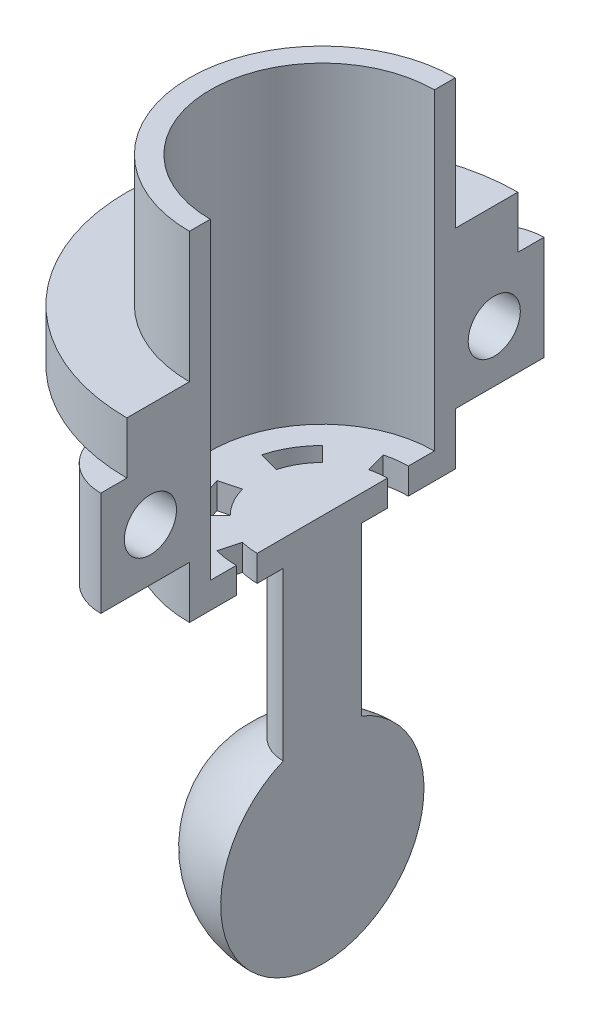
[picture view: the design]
ISO-10303-21;
HEADER;
FILE_DESCRIPTION(('STEP AP214'),'2;1');
FILE_NAME('part.step','',(''),(''),'','','');
FILE_SCHEMA(('AUTOMOTIVE_DESIGN { 1 0 10303 214 1 1 1 1 }'));
ENDSEC;
DATA;
#1=APPLICATION_CONTEXT('core data for automotive mechanical design processes');
#2=APPLICATION_PROTOCOL_DEFINITION('international standard','automotive_design',2000,#1);
#3=PRODUCT_CONTEXT('',#1,'mechanical');
#4=PRODUCT('Part','Part','',(#3));
#5=PRODUCT_RELATED_PRODUCT_CATEGORY('part','',(#4));
#6=PRODUCT_DEFINITION_FORMATION('','',#4);
#7=PRODUCT_DEFINITION_CONTEXT('part definition',#1,'design');
#8=PRODUCT_DEFINITION('design','',#6,#7);
#9=PRODUCT_DEFINITION_SHAPE('','',#8);
#10=(LENGTH_UNIT() NAMED_UNIT(*) SI_UNIT(.MILLI.,.METRE.));
#11=(NAMED_UNIT(*) PLANE_ANGLE_UNIT() SI_UNIT($,.RADIAN.));
#12=(NAMED_UNIT(*) SI_UNIT($,.STERADIAN.) SOLID_ANGLE_UNIT());
#13=UNCERTAINTY_MEASURE_WITH_UNIT(LENGTH_MEASURE(1.E-05),#10,'distance_accuracy_value','');
#14=(GEOMETRIC_REPRESENTATION_CONTEXT(3) GLOBAL_UNCERTAINTY_ASSIGNED_CONTEXT((#13)) GLOBAL_UNIT_ASSIGNED_CONTEXT((#10,
#11,#12)) REPRESENTATION_CONTEXT('',''));
#15=CARTESIAN_POINT('',(0.,0.,0.));
#16=DIRECTION('',(0.,0.,1.));
#17=DIRECTION('',(1.,0.,0.));
#18=AXIS2_PLACEMENT_3D('',#15,#16,#17);
#19=CARTESIAN_POINT('',(0.,0.,0.));
#20=DIRECTION('',(1.,0.,0.));
#21=DIRECTION('',(0.,0.,-1.));
#22=AXIS2_PLACEMENT_3D('',#19,#20,#21);
#23=PLANE('',#22);
#24=DIRECTION('',(0.,0.,-1.));
#25=VECTOR('',#24,1.);
#26=CARTESIAN_POINT('',(0.,1.,0.));
#27=LINE('',#26,#25);
#28=CARTESIAN_POINT('',(0.,1.,2.5));
#29=VERTEX_POINT('',#28);
#30=CARTESIAN_POINT('',(0.,1.,-2.5));
#31=VERTEX_POINT('',#30);
#32=EDGE_CURVE('E470',#29,#31,#27,.T.);
#33=ORIENTED_EDGE('',*,*,#32,.F.);
#34=DIRECTION('',(0.,1.,0.));
#35=VECTOR('',#34,1.);
#36=CARTESIAN_POINT('',(0.,0.,2.5));
#37=LINE('',#36,#35);
#38=CARTESIAN_POINT('',(0.,0.,2.5));
#39=VERTEX_POINT('',#38);
#40=EDGE_CURVE('E451',#39,#29,#37,.T.);
#41=ORIENTED_EDGE('',*,*,#40,.F.);
#42=DIRECTION('',(0.,0.,-1.));
#43=VECTOR('',#42,1.);
#44=CARTESIAN_POINT('',(0.,0.,0.));
#45=LINE('',#44,#43);
#46=CARTESIAN_POINT('',(0.,0.,1.5));
#47=VERTEX_POINT('',#46);
#48=EDGE_CURVE('E663',#39,#47,#45,.T.);
#49=ORIENTED_EDGE('',*,*,#48,.T.);
#50=DIRECTION('',(0.,1.,0.));
#51=VECTOR('',#50,1.);
#52=CARTESIAN_POINT('',(0.,0.,1.5));
#53=LINE('',#52,#51);
#54=CARTESIAN_POINT('',(0.,-6.4,1.5));
#55=VERTEX_POINT('',#54);
#56=EDGE_CURVE('E437',#55,#47,#53,.T.);
#57=ORIENTED_EDGE('',*,*,#56,.F.);
#58=CARTESIAN_POINT('',(0.,-10.,0.));
#59=DIRECTION('',(1.,0.,0.));
#60=DIRECTION('',(0.,0.,-1.));
#61=AXIS2_PLACEMENT_3D('',#58,#59,#60);
#62=CIRCLE('',#61,3.9);
#63=CARTESIAN_POINT('',(0.,-6.4,-1.5));
#64=VERTEX_POINT('',#63);
#65=EDGE_CURVE('E434',#64,#55,#62,.F.);
#66=ORIENTED_EDGE('',*,*,#65,.F.);
#67=DIRECTION('',(0.,1.,0.));
#68=VECTOR('',#67,1.);
#69=CARTESIAN_POINT('',(0.,0.,-1.5));
#70=LINE('',#69,#68);
#71=CARTESIAN_POINT('',(0.,0.,-1.5));
#72=VERTEX_POINT('',#71);
#73=EDGE_CURVE('E440',#72,#64,#70,.F.);
#74=ORIENTED_EDGE('',*,*,#73,.F.);
#75=CARTESIAN_POINT('',(0.,0.,-2.5));
#76=VERTEX_POINT('',#75);
#77=EDGE_CURVE('E484',#72,#76,#45,.T.);
#78=ORIENTED_EDGE('',*,*,#77,.T.);
#79=DIRECTION('',(0.,1.,0.));
#80=VECTOR('',#79,1.);
#81=CARTESIAN_POINT('',(0.,0.,-2.5));
#82=LINE('',#81,#80);
#83=EDGE_CURVE('E448',#31,#76,#82,.F.);
#84=ORIENTED_EDGE('',*,*,#83,.F.);
#85=EDGE_LOOP('',(#33,#41,#49,#57,#66,#74,#78,#84));
#86=FACE_BOUND('',#85,.T.);
#87=ADVANCED_FACE('F47',(#86),#23,.T.);
#88=CARTESIAN_POINT('',(0.,0.,5.1));
#89=VERTEX_POINT('',#88);
#90=CARTESIAN_POINT('',(0.,0.,3.3));
#91=VERTEX_POINT('',#90);
#92=EDGE_CURVE('E479',#89,#91,#45,.T.);
#93=ORIENTED_EDGE('',*,*,#92,.T.);
#94=DIRECTION('',(0.,1.,0.));
#95=VECTOR('',#94,1.);
#96=CARTESIAN_POINT('',(0.,0.,3.3));
#97=LINE('',#96,#95);
#98=CARTESIAN_POINT('',(0.,1.,3.3));
#99=VERTEX_POINT('',#98);
#100=EDGE_CURVE('E493',#91,#99,#97,.T.);
#101=ORIENTED_EDGE('',*,*,#100,.T.);
#102=CARTESIAN_POINT('',(0.,1.,4.3));
#103=VERTEX_POINT('',#102);
#104=EDGE_CURVE('E466',#103,#99,#27,.T.);
#105=ORIENTED_EDGE('',*,*,#104,.F.);
#106=DIRECTION('',(0.,-1.,0.));
#107=VECTOR('',#106,1.);
#108=CARTESIAN_POINT('',(0.,13.,4.3));
#109=LINE('',#108,#107);
#110=CARTESIAN_POINT('',(0.,13.,4.3));
#111=VERTEX_POINT('',#110);
#112=EDGE_CURVE('E462',#111,#103,#109,.T.);
#113=ORIENTED_EDGE('',*,*,#112,.F.);
#114=DIRECTION('',(0.,0.,-1.));
#115=VECTOR('',#114,1.);
#116=CARTESIAN_POINT('',(0.,13.,0.));
#117=LINE('',#116,#115);
#118=CARTESIAN_POINT('',(0.,13.,5.1));
#119=VERTEX_POINT('',#118);
#120=EDGE_CURVE('E455',#119,#111,#117,.T.);
#121=ORIENTED_EDGE('',*,*,#120,.F.);
#122=DIRECTION('',(0.,-1.,0.));
#123=VECTOR('',#122,1.);
#124=CARTESIAN_POINT('',(0.,1.,5.1));
#125=LINE('',#124,#123);
#126=CARTESIAN_POINT('',(0.,8.,5.1));
#127=VERTEX_POINT('',#126);
#128=EDGE_CURVE('E485',#119,#127,#125,.T.);
#129=ORIENTED_EDGE('',*,*,#128,.T.);
#130=DIRECTION('',(0.,0.,-1.));
#131=VECTOR('',#130,1.);
#132=CARTESIAN_POINT('',(0.,8.,0.));
#133=LINE('',#132,#131);
#134=CARTESIAN_POINT('',(0.,8.,7.5));
#135=VERTEX_POINT('',#134);
#136=EDGE_CURVE('E445',#135,#127,#133,.T.);
#137=ORIENTED_EDGE('',*,*,#136,.F.);
#138=DIRECTION('',(0.,-1.,0.));
#139=VECTOR('',#138,1.);
#140=CARTESIAN_POINT('',(0.,8.,7.5));
#141=LINE('',#140,#139);
#142=CARTESIAN_POINT('',(0.,6.,7.5));
#143=VERTEX_POINT('',#142);
#144=EDGE_CURVE('E299',#135,#143,#141,.T.);
#145=ORIENTED_EDGE('',*,*,#144,.T.);
#146=DIRECTION('',(0.,0.,-1.));
#147=VECTOR('',#146,1.);
#148=CARTESIAN_POINT('',(0.,6.,-7.502));
#149=LINE('',#148,#147);
#150=CARTESIAN_POINT('',(0.,6.,8.5));
#151=VERTEX_POINT('',#150);
#152=EDGE_CURVE('E427',#151,#143,#149,.T.);
#153=ORIENTED_EDGE('',*,*,#152,.F.);
#154=DIRECTION('',(0.,1.,0.));
#155=VECTOR('',#154,1.);
#156=CARTESIAN_POINT('',(0.,6.,8.5));
#157=LINE('',#156,#155);
#158=CARTESIAN_POINT('',(0.,2.,8.5));
#159=VERTEX_POINT('',#158);
#160=EDGE_CURVE('E409',#159,#151,#157,.T.);
#161=ORIENTED_EDGE('',*,*,#160,.F.);
#162=DIRECTION('',(0.,0.,1.));
#163=VECTOR('',#162,1.);
#164=CARTESIAN_POINT('',(0.,2.,-7.502));
#165=LINE('',#164,#163);
#166=CARTESIAN_POINT('',(0.,2.,5.1));
#167=VERTEX_POINT('',#166);
#168=EDGE_CURVE('E431',#167,#159,#165,.T.);
#169=ORIENTED_EDGE('',*,*,#168,.F.);
#170=DIRECTION('',(0.,-1.,0.));
#171=VECTOR('',#170,1.);
#172=CARTESIAN_POINT('',(0.,1.,5.1));
#173=LINE('',#172,#171);
#174=EDGE_CURVE('E471',#167,#89,#173,.T.);
#175=ORIENTED_EDGE('',*,*,#174,.T.);
#176=EDGE_LOOP('',(#93,#101,#105,#113,#121,#129,#137,#145,#153,#161,#169,#175));
#177=FACE_BOUND('',#176,.T.);
#178=CARTESIAN_POINT('',(0.,4.,6.59574082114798));
#179=DIRECTION('',(1.,0.,0.));
#180=DIRECTION('',(0.,1.,0.));
#181=AXIS2_PLACEMENT_3D('',#178,#179,#180);
#182=CIRCLE('',#181,1.);
#183=CARTESIAN_POINT('',(0.,5.,6.59574082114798));
#184=VERTEX_POINT('',#183);
#185=EDGE_CURVE('E405',#184,#184,#182,.T.);
#186=ORIENTED_EDGE('',*,*,#185,.F.);
#187=EDGE_LOOP('',(#186));
#188=FACE_BOUND('',#187,.T.);
#189=ADVANCED_FACE('F508',(#177,#188),#23,.T.);
#190=CARTESIAN_POINT('',(0.,1.,-3.3));
#191=VERTEX_POINT('',#190);
#192=CARTESIAN_POINT('',(0.,1.,-4.3));
#193=VERTEX_POINT('',#192);
#194=EDGE_CURVE('E465',#191,#193,#27,.T.);
#195=ORIENTED_EDGE('',*,*,#194,.F.);
#196=DIRECTION('',(0.,1.,0.));
#197=VECTOR('',#196,1.);
#198=CARTESIAN_POINT('',(0.,0.,-3.3));
#199=LINE('',#198,#197);
#200=CARTESIAN_POINT('',(0.,0.,-3.3));
#201=VERTEX_POINT('',#200);
#202=EDGE_CURVE('E497',#191,#201,#199,.F.);
#203=ORIENTED_EDGE('',*,*,#202,.T.);
#204=CARTESIAN_POINT('',(0.,0.,-5.1));
#205=VERTEX_POINT('',#204);
#206=EDGE_CURVE('E480',#201,#205,#45,.T.);
#207=ORIENTED_EDGE('',*,*,#206,.T.);
#208=DIRECTION('',(0.,-1.,0.));
#209=VECTOR('',#208,1.);
#210=CARTESIAN_POINT('',(0.,1.,-5.1));
#211=LINE('',#210,#209);
#212=CARTESIAN_POINT('',(0.,2.,-5.1));
#213=VERTEX_POINT('',#212);
#214=EDGE_CURVE('E475',#205,#213,#211,.F.);
#215=ORIENTED_EDGE('',*,*,#214,.T.);
#216=DIRECTION('',(0.,0.,-1.));
#217=VECTOR('',#216,1.);
#218=CARTESIAN_POINT('',(0.,2.,8.502));
#219=LINE('',#218,#217);
#220=CARTESIAN_POINT('',(0.,2.,-8.5));
#221=VERTEX_POINT('',#220);
#222=EDGE_CURVE('E300',#213,#221,#219,.T.);
#223=ORIENTED_EDGE('',*,*,#222,.T.);
#224=DIRECTION('',(0.,1.,0.));
#225=VECTOR('',#224,1.);
#226=CARTESIAN_POINT('',(0.,0.,-8.5));
#227=LINE('',#226,#225);
#228=CARTESIAN_POINT('',(0.,6.,-8.5));
#229=VERTEX_POINT('',#228);
#230=EDGE_CURVE('E11',#229,#221,#227,.F.);
#231=ORIENTED_EDGE('',*,*,#230,.F.);
#232=DIRECTION('',(0.,0.,1.));
#233=VECTOR('',#232,1.);
#234=CARTESIAN_POINT('',(0.,6.,8.502));
#235=LINE('',#234,#233);
#236=CARTESIAN_POINT('',(0.,6.,-7.5));
#237=VERTEX_POINT('',#236);
#238=EDGE_CURVE('E281',#229,#237,#235,.T.);
#239=ORIENTED_EDGE('',*,*,#238,.T.);
#240=DIRECTION('',(0.,-1.,0.));
#241=VECTOR('',#240,1.);
#242=CARTESIAN_POINT('',(0.,8.,-7.5));
#243=LINE('',#242,#241);
#244=CARTESIAN_POINT('',(0.,8.,-7.5));
#245=VERTEX_POINT('',#244);
#246=EDGE_CURVE('E293',#237,#245,#243,.F.);
#247=ORIENTED_EDGE('',*,*,#246,.T.);
#248=CARTESIAN_POINT('',(0.,8.,-5.1));
#249=VERTEX_POINT('',#248);
#250=EDGE_CURVE('E444',#249,#245,#133,.T.);
#251=ORIENTED_EDGE('',*,*,#250,.F.);
#252=DIRECTION('',(0.,-1.,0.));
#253=VECTOR('',#252,1.);
#254=CARTESIAN_POINT('',(0.,1.,-5.1));
#255=LINE('',#254,#253);
#256=CARTESIAN_POINT('',(0.,13.,-5.1));
#257=VERTEX_POINT('',#256);
#258=EDGE_CURVE('E489',#249,#257,#255,.F.);
#259=ORIENTED_EDGE('',*,*,#258,.T.);
#260=CARTESIAN_POINT('',(0.,13.,-4.3));
#261=VERTEX_POINT('',#260);
#262=EDGE_CURVE('E454',#261,#257,#117,.T.);
#263=ORIENTED_EDGE('',*,*,#262,.F.);
#264=DIRECTION('',(0.,-1.,0.));
#265=VECTOR('',#264,1.);
#266=CARTESIAN_POINT('',(0.,13.,-4.3));
#267=LINE('',#266,#265);
#268=EDGE_CURVE('E458',#193,#261,#267,.F.);
#269=ORIENTED_EDGE('',*,*,#268,.F.);
#270=EDGE_LOOP('',(#195,#203,#207,#215,#223,#231,#239,#247,#251,#259,#263,#269));
#271=FACE_BOUND('',#270,.T.);
#272=CARTESIAN_POINT('',(0.,4.,-6.59574082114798));
#273=DIRECTION('',(-1.,0.,0.));
#274=DIRECTION('',(0.,1.,0.));
#275=AXIS2_PLACEMENT_3D('',#272,#273,#274);
#276=CIRCLE('',#275,1.);
#277=CARTESIAN_POINT('',(0.,5.,-6.59574082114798));
#278=VERTEX_POINT('',#277);
#279=EDGE_CURVE('E57',#278,#278,#276,.T.);
#280=ORIENTED_EDGE('',*,*,#279,.T.);
#281=EDGE_LOOP('',(#280));
#282=FACE_BOUND('',#281,.T.);
#283=ADVANCED_FACE('F303',(#271,#282),#23,.T.);
#284=CARTESIAN_POINT('',(0.,0.,0.));
#285=DIRECTION('',(0.,1.,0.));
#286=DIRECTION('',(0.,0.,1.));
#287=AXIS2_PLACEMENT_3D('',#284,#285,#286);
#288=CYLINDRICAL_SURFACE('',#287,3.3);
#289=CARTESIAN_POINT('',(0.,1.,0.));
#290=DIRECTION('',(0.,1.,0.));
#291=DIRECTION('',(0.,0.,1.));
#292=AXIS2_PLACEMENT_3D('',#289,#290,#291);
#293=CIRCLE('',#292,3.3);
#294=CARTESIAN_POINT('',(-2.33345237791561,1.,-2.33345237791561));
#295=VERTEX_POINT('',#294);
#296=CARTESIAN_POINT('',(-3.18755522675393,1.,-0.854102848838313));
#297=VERTEX_POINT('',#296);
#298=EDGE_CURVE('E585',#295,#297,#293,.T.);
#299=ORIENTED_EDGE('',*,*,#298,.T.);
#300=DIRECTION('',(0.,1.,0.));
#301=VECTOR('',#300,1.);
#302=CARTESIAN_POINT('',(-3.18755522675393,0.,-0.854102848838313));
#303=LINE('',#302,#301);
#304=CARTESIAN_POINT('',(-3.18755522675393,0.,-0.854102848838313));
#305=VERTEX_POINT('',#304);
#306=EDGE_CURVE('E614',#305,#297,#303,.T.);
#307=ORIENTED_EDGE('',*,*,#306,.F.);
#308=CARTESIAN_POINT('',(0.,0.,0.));
#309=DIRECTION('',(0.,1.,0.));
#310=DIRECTION('',(0.,0.,1.));
#311=AXIS2_PLACEMENT_3D('',#308,#309,#310);
#312=CIRCLE('',#311,3.3);
#313=CARTESIAN_POINT('',(-2.33345237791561,0.,-2.33345237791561));
#314=VERTEX_POINT('',#313);
#315=EDGE_CURVE('E599',#314,#305,#312,.T.);
#316=ORIENTED_EDGE('',*,*,#315,.F.);
#317=DIRECTION('',(0.,1.,0.));
#318=VECTOR('',#317,1.);
#319=CARTESIAN_POINT('',(-2.33345237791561,0.,-2.33345237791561));
#320=LINE('',#319,#318);
#321=EDGE_CURVE('E611',#314,#295,#320,.T.);
#322=ORIENTED_EDGE('',*,*,#321,.T.);
#323=EDGE_LOOP('',(#299,#307,#316,#322));
#324=FACE_BOUND('',#323,.T.);
#325=ADVANCED_FACE('F721',(#324),#288,.F.);
#326=CARTESIAN_POINT('',(0.,0.,0.));
#327=DIRECTION('',(-0.258819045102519,0.,0.965925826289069));
#328=DIRECTION('',(0.965925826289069,0.,0.258819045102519));
#329=AXIS2_PLACEMENT_3D('',#326,#327,#328);
#330=PLANE('',#329);
#331=DIRECTION('',(0.965925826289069,0.,0.258819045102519));
#332=VECTOR('',#331,1.);
#333=CARTESIAN_POINT('',(0.,1.,0.));
#334=LINE('',#333,#332);
#335=CARTESIAN_POINT('',(-2.41481456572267,1.,-0.647047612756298));
#336=VERTEX_POINT('',#335);
#337=EDGE_CURVE('E589',#297,#336,#334,.T.);
#338=ORIENTED_EDGE('',*,*,#337,.T.);
#339=DIRECTION('',(0.,1.,0.));
#340=VECTOR('',#339,1.);
#341=CARTESIAN_POINT('',(-2.41481456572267,0.,-0.647047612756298));
#342=LINE('',#341,#340);
#343=CARTESIAN_POINT('',(-2.41481456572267,0.,-0.647047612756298));
#344=VERTEX_POINT('',#343);
#345=EDGE_CURVE('E330',#344,#336,#342,.T.);
#346=ORIENTED_EDGE('',*,*,#345,.F.);
#347=DIRECTION('',(0.965925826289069,0.,0.258819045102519));
#348=VECTOR('',#347,1.);
#349=CARTESIAN_POINT('',(0.,0.,0.));
#350=LINE('',#349,#348);
#351=EDGE_CURVE('E603',#305,#344,#350,.T.);
#352=ORIENTED_EDGE('',*,*,#351,.F.);
#353=ORIENTED_EDGE('',*,*,#306,.T.);
#354=EDGE_LOOP('',(#338,#346,#352,#353));
#355=FACE_BOUND('',#354,.T.);
#356=ADVANCED_FACE('F723',(#355),#330,.F.);
#357=CARTESIAN_POINT('',(0.,0.,0.));
#358=DIRECTION('',(0.,1.,0.));
#359=DIRECTION('',(0.,0.,1.));
#360=AXIS2_PLACEMENT_3D('',#357,#358,#359);
#361=CYLINDRICAL_SURFACE('',#360,2.5);
#362=CARTESIAN_POINT('',(0.,1.,0.));
#363=DIRECTION('',(0.,1.,0.));
#364=DIRECTION('',(0.,0.,1.));
#365=AXIS2_PLACEMENT_3D('',#362,#363,#364);
#366=CIRCLE('',#365,2.5);
#367=CARTESIAN_POINT('',(-1.76776695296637,1.,-1.76776695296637));
#368=VERTEX_POINT('',#367);
#369=EDGE_CURVE('E336',#368,#336,#366,.T.);
#370=ORIENTED_EDGE('',*,*,#369,.F.);
#371=DIRECTION('',(0.,1.,0.));
#372=VECTOR('',#371,1.);
#373=CARTESIAN_POINT('',(-1.76776695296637,0.,-1.76776695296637));
#374=LINE('',#373,#372);
#375=CARTESIAN_POINT('',(-1.76776695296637,0.,-1.76776695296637));
#376=VERTEX_POINT('',#375);
#377=EDGE_CURVE('E607',#376,#368,#374,.T.);
#378=ORIENTED_EDGE('',*,*,#377,.F.);
#379=CARTESIAN_POINT('',(0.,0.,0.));
#380=DIRECTION('',(0.,1.,0.));
#381=DIRECTION('',(0.,0.,1.));
#382=AXIS2_PLACEMENT_3D('',#379,#380,#381);
#383=CIRCLE('',#382,2.5);
#384=EDGE_CURVE('E593',#376,#344,#383,.T.);
#385=ORIENTED_EDGE('',*,*,#384,.T.);
#386=ORIENTED_EDGE('',*,*,#345,.T.);
#387=EDGE_LOOP('',(#370,#378,#385,#386));
#388=FACE_BOUND('',#387,.T.);
#389=ADVANCED_FACE('F730',(#388),#361,.T.);
#390=CARTESIAN_POINT('',(0.,0.,0.));
#391=DIRECTION('',(-0.707106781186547,0.,0.707106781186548));
#392=DIRECTION('',(0.707106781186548,0.,0.707106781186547));
#393=AXIS2_PLACEMENT_3D('',#390,#391,#392);
#394=PLANE('',#393);
#395=DIRECTION('',(0.707106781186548,0.,0.707106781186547));
#396=VECTOR('',#395,1.);
#397=CARTESIAN_POINT('',(0.,1.,0.));
#398=LINE('',#397,#396);
#399=EDGE_CURVE('E581',#295,#368,#398,.T.);
#400=ORIENTED_EDGE('',*,*,#399,.F.);
#401=ORIENTED_EDGE('',*,*,#321,.F.);
#402=DIRECTION('',(0.707106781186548,0.,0.707106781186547));
#403=VECTOR('',#402,1.);
#404=CARTESIAN_POINT('',(0.,0.,0.));
#405=LINE('',#404,#403);
#406=EDGE_CURVE('E596',#314,#376,#405,.T.);
#407=ORIENTED_EDGE('',*,*,#406,.T.);
#408=ORIENTED_EDGE('',*,*,#377,.T.);
#409=EDGE_LOOP('',(#400,#401,#407,#408));
#410=FACE_BOUND('',#409,.T.);
#411=ADVANCED_FACE('F735',(#410),#394,.T.);
#412=CARTESIAN_POINT('',(0.,0.,0.));
#413=DIRECTION('',(0.,1.,0.));
#414=DIRECTION('',(0.,0.,1.));
#415=AXIS2_PLACEMENT_3D('',#412,#413,#414);
#416=CYLINDRICAL_SURFACE('',#415,3.3);
#417=CARTESIAN_POINT('',(0.,1.,0.));
#418=DIRECTION('',(0.,1.,0.));
#419=DIRECTION('',(0.,0.,1.));
#420=AXIS2_PLACEMENT_3D('',#417,#418,#419);
#421=CIRCLE('',#420,3.3);
#422=CARTESIAN_POINT('',(-3.18755522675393,1.,0.854102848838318));
#423=VERTEX_POINT('',#422);
#424=CARTESIAN_POINT('',(-2.3334523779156,1.,2.33345237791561));
#425=VERTEX_POINT('',#424);
#426=EDGE_CURVE('E557',#423,#425,#421,.T.);
#427=ORIENTED_EDGE('',*,*,#426,.T.);
#428=DIRECTION('',(0.,1.,0.));
#429=VECTOR('',#428,1.);
#430=CARTESIAN_POINT('',(-2.3334523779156,0.,2.33345237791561));
#431=LINE('',#430,#429);
#432=CARTESIAN_POINT('',(-2.3334523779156,0.,2.33345237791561));
#433=VERTEX_POINT('',#432);
#434=EDGE_CURVE('E529',#433,#425,#431,.T.);
#435=ORIENTED_EDGE('',*,*,#434,.F.);
#436=CARTESIAN_POINT('',(0.,0.,0.));
#437=DIRECTION('',(0.,1.,0.));
#438=DIRECTION('',(0.,0.,1.));
#439=AXIS2_PLACEMENT_3D('',#436,#437,#438);
#440=CIRCLE('',#439,3.3);
#441=CARTESIAN_POINT('',(-3.18755522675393,0.,0.854102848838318));
#442=VERTEX_POINT('',#441);
#443=EDGE_CURVE('E543',#442,#433,#440,.T.);
#444=ORIENTED_EDGE('',*,*,#443,.F.);
#445=DIRECTION('',(0.,1.,0.));
#446=VECTOR('',#445,1.);
#447=CARTESIAN_POINT('',(-3.18755522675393,0.,0.854102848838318));
#448=LINE('',#447,#446);
#449=EDGE_CURVE('E532',#442,#423,#448,.T.);
#450=ORIENTED_EDGE('',*,*,#449,.T.);
#451=EDGE_LOOP('',(#427,#435,#444,#450));
#452=FACE_BOUND('',#451,.T.);
#453=ADVANCED_FACE('F745',(#452),#416,.F.);
#454=CARTESIAN_POINT('',(0.,0.,0.));
#455=DIRECTION('',(0.707106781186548,0.,0.707106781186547));
#456=DIRECTION('',(0.707106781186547,0.,-0.707106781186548));
#457=AXIS2_PLACEMENT_3D('',#454,#455,#456);
#458=PLANE('',#457);
#459=DIRECTION('',(0.707106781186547,0.,-0.707106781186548));
#460=VECTOR('',#459,1.);
#461=CARTESIAN_POINT('',(0.,1.,0.));
#462=LINE('',#461,#460);
#463=CARTESIAN_POINT('',(-1.76776695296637,1.,1.76776695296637));
#464=VERTEX_POINT('',#463);
#465=EDGE_CURVE('E553',#425,#464,#462,.T.);
#466=ORIENTED_EDGE('',*,*,#465,.T.);
#467=DIRECTION('',(0.,1.,0.));
#468=VECTOR('',#467,1.);
#469=CARTESIAN_POINT('',(-1.76776695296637,0.,1.76776695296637));
#470=LINE('',#469,#468);
#471=CARTESIAN_POINT('',(-1.76776695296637,0.,1.76776695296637));
#472=VERTEX_POINT('',#471);
#473=EDGE_CURVE('E353',#472,#464,#470,.T.);
#474=ORIENTED_EDGE('',*,*,#473,.F.);
#475=DIRECTION('',(0.707106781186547,0.,-0.707106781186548));
#476=VECTOR('',#475,1.);
#477=CARTESIAN_POINT('',(0.,0.,0.));
#478=LINE('',#477,#476);
#479=EDGE_CURVE('E539',#433,#472,#478,.T.);
#480=ORIENTED_EDGE('',*,*,#479,.F.);
#481=ORIENTED_EDGE('',*,*,#434,.T.);
#482=EDGE_LOOP('',(#466,#474,#480,#481));
#483=FACE_BOUND('',#482,.T.);
#484=ADVANCED_FACE('F741',(#483),#458,.F.);
#485=CARTESIAN_POINT('',(0.,0.,0.));
#486=DIRECTION('',(0.,1.,0.));
#487=DIRECTION('',(0.,0.,1.));
#488=AXIS2_PLACEMENT_3D('',#485,#486,#487);
#489=CYLINDRICAL_SURFACE('',#488,2.5);
#490=CARTESIAN_POINT('',(0.,1.,0.));
#491=DIRECTION('',(0.,1.,0.));
#492=DIRECTION('',(0.,0.,1.));
#493=AXIS2_PLACEMENT_3D('',#490,#491,#492);
#494=CIRCLE('',#493,2.5);
#495=CARTESIAN_POINT('',(-2.41481456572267,1.,0.647047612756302));
#496=VERTEX_POINT('',#495);
#497=EDGE_CURVE('E565',#496,#464,#494,.T.);
#498=ORIENTED_EDGE('',*,*,#497,.F.);
#499=DIRECTION('',(0.,1.,0.));
#500=VECTOR('',#499,1.);
#501=CARTESIAN_POINT('',(-2.41481456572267,0.,0.647047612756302));
#502=LINE('',#501,#500);
#503=CARTESIAN_POINT('',(-2.41481456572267,0.,0.647047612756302));
#504=VERTEX_POINT('',#503);
#505=EDGE_CURVE('E535',#504,#496,#502,.T.);
#506=ORIENTED_EDGE('',*,*,#505,.F.);
#507=CARTESIAN_POINT('',(0.,0.,0.));
#508=DIRECTION('',(0.,1.,0.));
#509=DIRECTION('',(0.,0.,1.));
#510=AXIS2_PLACEMENT_3D('',#507,#508,#509);
#511=CIRCLE('',#510,2.5);
#512=EDGE_CURVE('E550',#504,#472,#511,.T.);
#513=ORIENTED_EDGE('',*,*,#512,.T.);
#514=ORIENTED_EDGE('',*,*,#473,.T.);
#515=EDGE_LOOP('',(#498,#506,#513,#514));
#516=FACE_BOUND('',#515,.T.);
#517=ADVANCED_FACE('F744',(#516),#489,.T.);
#518=CARTESIAN_POINT('',(0.,0.,0.));
#519=DIRECTION('',(0.258819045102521,0.,0.965925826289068));
#520=DIRECTION('',(0.965925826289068,0.,-0.258819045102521));
#521=AXIS2_PLACEMENT_3D('',#518,#519,#520);
#522=PLANE('',#521);
#523=DIRECTION('',(0.965925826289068,0.,-0.258819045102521));
#524=VECTOR('',#523,1.);
#525=CARTESIAN_POINT('',(0.,1.,0.));
#526=LINE('',#525,#524);
#527=EDGE_CURVE('E561',#423,#496,#526,.T.);
#528=ORIENTED_EDGE('',*,*,#527,.F.);
#529=ORIENTED_EDGE('',*,*,#449,.F.);
#530=DIRECTION('',(0.965925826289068,0.,-0.258819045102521));
#531=VECTOR('',#530,1.);
#532=CARTESIAN_POINT('',(0.,0.,0.));
#533=LINE('',#532,#531);
#534=EDGE_CURVE('E547',#442,#504,#533,.T.);
#535=ORIENTED_EDGE('',*,*,#534,.T.);
#536=ORIENTED_EDGE('',*,*,#505,.T.);
#537=EDGE_LOOP('',(#528,#529,#535,#536));
#538=FACE_BOUND('',#537,.T.);
#539=ADVANCED_FACE('F750',(#538),#522,.T.);
#540=CARTESIAN_POINT('',(0.,0.,0.));
#541=DIRECTION('',(0.965925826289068,0.,0.258819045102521));
#542=DIRECTION('',(0.258819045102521,0.,-0.965925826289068));
#543=AXIS2_PLACEMENT_3D('',#540,#541,#542);
#544=PLANE('',#543);
#545=DIRECTION('',(0.258819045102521,0.,-0.965925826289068));
#546=VECTOR('',#545,1.);
#547=CARTESIAN_POINT('',(0.,1.,0.));
#548=LINE('',#547,#546);
#549=CARTESIAN_POINT('',(-0.85410284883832,1.,3.18755522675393));
#550=VERTEX_POINT('',#549);
#551=CARTESIAN_POINT('',(-0.647047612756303,1.,2.41481456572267));
#552=VERTEX_POINT('',#551);
#553=EDGE_CURVE('E335',#550,#552,#548,.T.);
#554=ORIENTED_EDGE('',*,*,#553,.F.);
#555=DIRECTION('',(0.,1.,0.));
#556=VECTOR('',#555,1.);
#557=CARTESIAN_POINT('',(-0.85410284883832,0.,3.18755522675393));
#558=LINE('',#557,#556);
#559=CARTESIAN_POINT('',(-0.85410284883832,0.,3.18755522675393));
#560=VERTEX_POINT('',#559);
#561=EDGE_CURVE('E569',#560,#550,#558,.T.);
#562=ORIENTED_EDGE('',*,*,#561,.F.);
#563=DIRECTION('',(0.258819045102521,0.,-0.965925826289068));
#564=VECTOR('',#563,1.);
#565=CARTESIAN_POINT('',(0.,0.,0.));
#566=LINE('',#565,#564);
#567=CARTESIAN_POINT('',(-0.647047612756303,0.,2.41481456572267));
#568=VERTEX_POINT('',#567);
#569=EDGE_CURVE('E344',#560,#568,#566,.T.);
#570=ORIENTED_EDGE('',*,*,#569,.T.);
#571=DIRECTION('',(0.,1.,0.));
#572=VECTOR('',#571,1.);
#573=CARTESIAN_POINT('',(-0.647047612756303,0.,2.41481456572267));
#574=LINE('',#573,#572);
#575=EDGE_CURVE('E348',#568,#552,#574,.T.);
#576=ORIENTED_EDGE('',*,*,#575,.T.);
#577=EDGE_LOOP('',(#554,#562,#570,#576));
#578=FACE_BOUND('',#577,.T.);
#579=ADVANCED_FACE('F696',(#578),#544,.T.);
#580=CARTESIAN_POINT('',(0.,0.,0.));
#581=DIRECTION('',(0.,1.,0.));
#582=DIRECTION('',(0.,0.,1.));
#583=AXIS2_PLACEMENT_3D('',#580,#581,#582);
#584=PLANE('',#583);
#585=ORIENTED_EDGE('',*,*,#384,.F.);
#586=ORIENTED_EDGE('',*,*,#406,.F.);
#587=ORIENTED_EDGE('',*,*,#315,.T.);
#588=ORIENTED_EDGE('',*,*,#351,.T.);
#589=EDGE_LOOP('',(#585,#586,#587,#588));
#590=FACE_BOUND('',#589,.T.);
#591=ORIENTED_EDGE('',*,*,#512,.F.);
#592=ORIENTED_EDGE('',*,*,#534,.F.);
#593=ORIENTED_EDGE('',*,*,#443,.T.);
#594=ORIENTED_EDGE('',*,*,#479,.T.);
#595=EDGE_LOOP('',(#591,#592,#593,#594));
#596=FACE_BOUND('',#595,.T.);
#597=ORIENTED_EDGE('',*,*,#92,.F.);
#598=CARTESIAN_POINT('',(0.,0.,0.));
#599=DIRECTION('',(0.,1.,0.));
#600=DIRECTION('',(0.,0.,1.));
#601=AXIS2_PLACEMENT_3D('',#598,#599,#600);
#602=CIRCLE('',#601,5.1);
#603=EDGE_CURVE('E319',#205,#89,#602,.T.);
#604=ORIENTED_EDGE('',*,*,#603,.F.);
#605=ORIENTED_EDGE('',*,*,#206,.F.);
#606=CARTESIAN_POINT('',(0.,0.,0.));
#607=DIRECTION('',(0.,1.,0.));
#608=DIRECTION('',(0.,0.,1.));
#609=AXIS2_PLACEMENT_3D('',#606,#607,#608);
#610=CIRCLE('',#609,3.3);
#611=CARTESIAN_POINT('',(-0.854102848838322,0.,-3.18755522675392));
#612=VERTEX_POINT('',#611);
#613=EDGE_CURVE('E361',#201,#612,#610,.T.);
#614=ORIENTED_EDGE('',*,*,#613,.T.);
#615=DIRECTION('',(0.258819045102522,0.,0.965925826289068));
#616=VECTOR('',#615,1.);
#617=CARTESIAN_POINT('',(-0.854102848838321,0.,-3.18755522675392));
#618=LINE('',#617,#616);
#619=CARTESIAN_POINT('',(-0.647047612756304,0.,-2.41481456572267));
#620=VERTEX_POINT('',#619);
#621=EDGE_CURVE('E360',#612,#620,#618,.T.);
#622=ORIENTED_EDGE('',*,*,#621,.T.);
#623=CARTESIAN_POINT('',(0.,0.,0.));
#624=DIRECTION('',(0.,1.,0.));
#625=DIRECTION('',(0.,0.,1.));
#626=AXIS2_PLACEMENT_3D('',#623,#624,#625);
#627=CIRCLE('',#626,2.5);
#628=EDGE_CURVE('E357',#76,#620,#627,.T.);
#629=ORIENTED_EDGE('',*,*,#628,.F.);
#630=ORIENTED_EDGE('',*,*,#77,.F.);
#631=CARTESIAN_POINT('',(0.,0.,0.));
#632=DIRECTION('',(0.,1.,0.));
#633=DIRECTION('',(0.,0.,1.));
#634=AXIS2_PLACEMENT_3D('',#631,#632,#633);
#635=CIRCLE('',#634,1.5);
#636=EDGE_CURVE('E372',#72,#47,#635,.T.);
#637=ORIENTED_EDGE('',*,*,#636,.T.);
#638=ORIENTED_EDGE('',*,*,#48,.F.);
#639=CARTESIAN_POINT('',(0.,0.,0.));
#640=DIRECTION('',(0.,1.,0.));
#641=DIRECTION('',(0.,0.,1.));
#642=AXIS2_PLACEMENT_3D('',#639,#640,#641);
#643=CIRCLE('',#642,2.5);
#644=EDGE_CURVE('E340',#568,#39,#643,.T.);
#645=ORIENTED_EDGE('',*,*,#644,.F.);
#646=ORIENTED_EDGE('',*,*,#569,.F.);
#647=CARTESIAN_POINT('',(0.,0.,0.));
#648=DIRECTION('',(0.,1.,0.));
#649=DIRECTION('',(0.,0.,1.));
#650=AXIS2_PLACEMENT_3D('',#647,#648,#649);
#651=CIRCLE('',#650,3.3);
#652=EDGE_CURVE('E345',#560,#91,#651,.T.);
#653=ORIENTED_EDGE('',*,*,#652,.T.);
#654=EDGE_LOOP('',(#597,#604,#605,#614,#622,#629,#630,#637,#638,#645,#646,#653));
#655=FACE_BOUND('',#654,.T.);
#656=ADVANCED_FACE('F674',(#590,#596,#655),#584,.F.);
#657=CARTESIAN_POINT('',(0.,0.,0.));
#658=DIRECTION('',(0.,1.,0.));
#659=DIRECTION('',(0.,0.,1.));
#660=AXIS2_PLACEMENT_3D('',#657,#658,#659);
#661=CYLINDRICAL_SURFACE('',#660,1.5);
#662=ORIENTED_EDGE('',*,*,#636,.F.);
#663=ORIENTED_EDGE('',*,*,#73,.T.);
#664=CARTESIAN_POINT('',(0.,-6.4,0.));
#665=DIRECTION('',(0.,1.,0.));
#666=DIRECTION('',(0.,0.,1.));
#667=AXIS2_PLACEMENT_3D('',#664,#665,#666);
#668=CIRCLE('',#667,1.5);
#669=EDGE_CURVE('E376',#64,#55,#668,.T.);
#670=ORIENTED_EDGE('',*,*,#669,.T.);
#671=ORIENTED_EDGE('',*,*,#56,.T.);
#672=EDGE_LOOP('',(#662,#663,#670,#671));
#673=FACE_BOUND('',#672,.T.);
#674=ADVANCED_FACE('F802',(#673),#661,.T.);
#675=CARTESIAN_POINT('',(0.,-10.,0.));
#676=DIRECTION('',(0.,1.,0.));
#677=DIRECTION('',(0.,0.,1.));
#678=AXIS2_PLACEMENT_3D('',#675,#676,#677);
#679=SPHERICAL_SURFACE('',#678,3.9);
#680=ORIENTED_EDGE('',*,*,#669,.F.);
#681=ORIENTED_EDGE('',*,*,#65,.T.);
#682=EDGE_LOOP('',(#680,#681));
#683=FACE_BOUND('',#682,.T.);
#684=ADVANCED_FACE('F740',(#683),#679,.T.);
#685=CARTESIAN_POINT('',(-0.854102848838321,0.,-3.18755522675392));
#686=DIRECTION('',(-0.965925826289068,0.,0.258819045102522));
#687=DIRECTION('',(0.258819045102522,0.,0.965925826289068));
#688=AXIS2_PLACEMENT_3D('',#685,#686,#687);
#689=PLANE('',#688);
#690=DIRECTION('',(0.258819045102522,0.,0.965925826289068));
#691=VECTOR('',#690,1.);
#692=CARTESIAN_POINT('',(-0.854102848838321,1.,-3.18755522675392));
#693=LINE('',#692,#691);
#694=CARTESIAN_POINT('',(-0.854102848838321,1.,-3.18755522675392));
#695=VERTEX_POINT('',#694);
#696=CARTESIAN_POINT('',(-0.647047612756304,1.,-2.41481456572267));
#697=VERTEX_POINT('',#696);
#698=EDGE_CURVE('E352',#695,#697,#693,.T.);
#699=ORIENTED_EDGE('',*,*,#698,.T.);
#700=DIRECTION('',(0.,1.,0.));
#701=VECTOR('',#700,1.);
#702=CARTESIAN_POINT('',(-0.647047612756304,0.,-2.41481456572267));
#703=LINE('',#702,#701);
#704=EDGE_CURVE('E366',#620,#697,#703,.T.);
#705=ORIENTED_EDGE('',*,*,#704,.F.);
#706=ORIENTED_EDGE('',*,*,#621,.F.);
#707=DIRECTION('',(0.,1.,0.));
#708=VECTOR('',#707,1.);
#709=CARTESIAN_POINT('',(-0.854102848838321,0.,-3.18755522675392));
#710=LINE('',#709,#708);
#711=EDGE_CURVE('E364',#612,#695,#710,.T.);
#712=ORIENTED_EDGE('',*,*,#711,.T.);
#713=EDGE_LOOP('',(#699,#705,#706,#712));
#714=FACE_BOUND('',#713,.T.);
#715=ADVANCED_FACE('F681',(#714),#689,.F.);
#716=CARTESIAN_POINT('',(0.,1.,0.));
#717=DIRECTION('',(0.,1.,0.));
#718=DIRECTION('',(0.,0.,1.));
#719=AXIS2_PLACEMENT_3D('',#716,#717,#718);
#720=PLANE('',#719);
#721=ORIENTED_EDGE('',*,*,#527,.T.);
#722=ORIENTED_EDGE('',*,*,#497,.T.);
#723=ORIENTED_EDGE('',*,*,#465,.F.);
#724=ORIENTED_EDGE('',*,*,#426,.F.);
#725=EDGE_LOOP('',(#721,#722,#723,#724));
#726=FACE_BOUND('',#725,.T.);
#727=ORIENTED_EDGE('',*,*,#399,.T.);
#728=ORIENTED_EDGE('',*,*,#369,.T.);
#729=ORIENTED_EDGE('',*,*,#337,.F.);
#730=ORIENTED_EDGE('',*,*,#298,.F.);
#731=EDGE_LOOP('',(#727,#728,#729,#730));
#732=FACE_BOUND('',#731,.T.);
#733=CARTESIAN_POINT('',(0.,1.,0.));
#734=DIRECTION('',(0.,1.,0.));
#735=DIRECTION('',(0.,0.,1.));
#736=AXIS2_PLACEMENT_3D('',#733,#734,#735);
#737=CIRCLE('',#736,4.3);
#738=EDGE_CURVE('E314',#103,#193,#737,.F.);
#739=ORIENTED_EDGE('',*,*,#738,.F.);
#740=ORIENTED_EDGE('',*,*,#104,.T.);
#741=CARTESIAN_POINT('',(0.,1.,0.));
#742=DIRECTION('',(0.,1.,0.));
#743=DIRECTION('',(0.,0.,1.));
#744=AXIS2_PLACEMENT_3D('',#741,#742,#743);
#745=CIRCLE('',#744,3.3);
#746=EDGE_CURVE('E337',#550,#99,#745,.T.);
#747=ORIENTED_EDGE('',*,*,#746,.F.);
#748=ORIENTED_EDGE('',*,*,#553,.T.);
#749=CARTESIAN_POINT('',(0.,1.,0.));
#750=DIRECTION('',(0.,1.,0.));
#751=DIRECTION('',(0.,0.,1.));
#752=AXIS2_PLACEMENT_3D('',#749,#750,#751);
#753=CIRCLE('',#752,2.5);
#754=EDGE_CURVE('E331',#552,#29,#753,.T.);
#755=ORIENTED_EDGE('',*,*,#754,.T.);
#756=ORIENTED_EDGE('',*,*,#32,.T.);
#757=CARTESIAN_POINT('',(0.,1.,0.));
#758=DIRECTION('',(0.,1.,0.));
#759=DIRECTION('',(0.,0.,1.));
#760=AXIS2_PLACEMENT_3D('',#757,#758,#759);
#761=CIRCLE('',#760,2.5);
#762=EDGE_CURVE('E349',#31,#697,#761,.T.);
#763=ORIENTED_EDGE('',*,*,#762,.T.);
#764=ORIENTED_EDGE('',*,*,#698,.F.);
#765=CARTESIAN_POINT('',(0.,1.,0.));
#766=DIRECTION('',(0.,1.,0.));
#767=DIRECTION('',(0.,0.,1.));
#768=AXIS2_PLACEMENT_3D('',#765,#766,#767);
#769=CIRCLE('',#768,3.3);
#770=EDGE_CURVE('E354',#191,#695,#769,.T.);
#771=ORIENTED_EDGE('',*,*,#770,.F.);
#772=ORIENTED_EDGE('',*,*,#194,.T.);
#773=EDGE_LOOP('',(#739,#740,#747,#748,#755,#756,#763,#764,#771,#772));
#774=FACE_BOUND('',#773,.T.);
#775=ADVANCED_FACE('F686',(#726,#732,#774),#720,.T.);
#776=CARTESIAN_POINT('',(0.,0.,0.));
#777=DIRECTION('',(0.,1.,0.));
#778=DIRECTION('',(0.,0.,1.));
#779=AXIS2_PLACEMENT_3D('',#776,#777,#778);
#780=CYLINDRICAL_SURFACE('',#779,3.3);
#781=ORIENTED_EDGE('',*,*,#202,.F.);
#782=ORIENTED_EDGE('',*,*,#770,.T.);
#783=ORIENTED_EDGE('',*,*,#711,.F.);
#784=ORIENTED_EDGE('',*,*,#613,.F.);
#785=EDGE_LOOP('',(#781,#782,#783,#784));
#786=FACE_BOUND('',#785,.T.);
#787=ADVANCED_FACE('F711',(#786),#780,.F.);
#788=CARTESIAN_POINT('',(0.,0.,0.));
#789=DIRECTION('',(0.,1.,0.));
#790=DIRECTION('',(0.,0.,1.));
#791=AXIS2_PLACEMENT_3D('',#788,#789,#790);
#792=CYLINDRICAL_SURFACE('',#791,2.5);
#793=ORIENTED_EDGE('',*,*,#762,.F.);
#794=ORIENTED_EDGE('',*,*,#83,.T.);
#795=ORIENTED_EDGE('',*,*,#628,.T.);
#796=ORIENTED_EDGE('',*,*,#704,.T.);
#797=EDGE_LOOP('',(#793,#794,#795,#796));
#798=FACE_BOUND('',#797,.T.);
#799=ADVANCED_FACE('F679',(#798),#792,.T.);
#800=CARTESIAN_POINT('',(0.,0.,0.));
#801=DIRECTION('',(0.,1.,0.));
#802=DIRECTION('',(0.,0.,1.));
#803=AXIS2_PLACEMENT_3D('',#800,#801,#802);
#804=CYLINDRICAL_SURFACE('',#803,3.3);
#805=ORIENTED_EDGE('',*,*,#100,.F.);
#806=ORIENTED_EDGE('',*,*,#652,.F.);
#807=ORIENTED_EDGE('',*,*,#561,.T.);
#808=ORIENTED_EDGE('',*,*,#746,.T.);
#809=EDGE_LOOP('',(#805,#806,#807,#808));
#810=FACE_BOUND('',#809,.T.);
#811=ADVANCED_FACE('F702',(#810),#804,.F.);
#812=CARTESIAN_POINT('',(0.,0.,0.));
#813=DIRECTION('',(0.,1.,0.));
#814=DIRECTION('',(0.,0.,1.));
#815=AXIS2_PLACEMENT_3D('',#812,#813,#814);
#816=CYLINDRICAL_SURFACE('',#815,2.5);
#817=ORIENTED_EDGE('',*,*,#644,.T.);
#818=ORIENTED_EDGE('',*,*,#40,.T.);
#819=ORIENTED_EDGE('',*,*,#754,.F.);
#820=ORIENTED_EDGE('',*,*,#575,.F.);
#821=EDGE_LOOP('',(#817,#818,#819,#820));
#822=FACE_BOUND('',#821,.T.);
#823=ADVANCED_FACE('F693',(#822),#816,.T.);
#824=CARTESIAN_POINT('',(0.,13.,0.));
#825=DIRECTION('',(0.,-1.,0.));
#826=DIRECTION('',(0.,0.,-1.));
#827=AXIS2_PLACEMENT_3D('',#824,#825,#826);
#828=CYLINDRICAL_SURFACE('',#827,4.3);
#829=CARTESIAN_POINT('',(0.,13.,0.));
#830=DIRECTION('',(0.,1.,0.));
#831=DIRECTION('',(0.,0.,1.));
#832=AXIS2_PLACEMENT_3D('',#829,#830,#831);
#833=CIRCLE('',#832,4.3);
#834=EDGE_CURVE('E326',#261,#111,#833,.T.);
#835=ORIENTED_EDGE('',*,*,#834,.T.);
#836=ORIENTED_EDGE('',*,*,#112,.T.);
#837=ORIENTED_EDGE('',*,*,#738,.T.);
#838=ORIENTED_EDGE('',*,*,#268,.T.);
#839=EDGE_LOOP('',(#835,#836,#837,#838));
#840=FACE_BOUND('',#839,.T.);
#841=ADVANCED_FACE('F865',(#840),#828,.F.);
#842=CARTESIAN_POINT('',(0.,1.,0.));
#843=DIRECTION('',(0.,-1.,0.));
#844=DIRECTION('',(0.,0.,-1.));
#845=AXIS2_PLACEMENT_3D('',#842,#843,#844);
#846=CYLINDRICAL_SURFACE('',#845,5.1);
#847=ORIENTED_EDGE('',*,*,#128,.F.);
#848=CARTESIAN_POINT('',(0.,13.,0.));
#849=DIRECTION('',(0.,1.,0.));
#850=DIRECTION('',(0.,0.,1.));
#851=AXIS2_PLACEMENT_3D('',#848,#849,#850);
#852=CIRCLE('',#851,5.1);
#853=EDGE_CURVE('E322',#257,#119,#852,.T.);
#854=ORIENTED_EDGE('',*,*,#853,.F.);
#855=ORIENTED_EDGE('',*,*,#258,.F.);
#856=CARTESIAN_POINT('',(0.,8.,0.));
#857=DIRECTION('',(0.,1.,0.));
#858=DIRECTION('',(0.,0.,1.));
#859=AXIS2_PLACEMENT_3D('',#856,#857,#858);
#860=CIRCLE('',#859,5.1);
#861=EDGE_CURVE('E368',#249,#127,#860,.T.);
#862=ORIENTED_EDGE('',*,*,#861,.T.);
#863=EDGE_LOOP('',(#847,#854,#855,#862));
#864=FACE_BOUND('',#863,.T.);
#865=ADVANCED_FACE('F874',(#864),#846,.T.);
#866=CARTESIAN_POINT('',(0.,8.,0.));
#867=DIRECTION('',(0.,1.,0.));
#868=DIRECTION('',(0.,0.,1.));
#869=AXIS2_PLACEMENT_3D('',#866,#867,#868);
#870=PLANE('',#869);
#871=CARTESIAN_POINT('',(0.,8.,0.));
#872=DIRECTION('',(0.,1.,0.));
#873=DIRECTION('',(0.,0.,1.));
#874=AXIS2_PLACEMENT_3D('',#871,#872,#873);
#875=CIRCLE('',#874,7.5);
#876=EDGE_CURVE('E289',#245,#135,#875,.T.);
#877=ORIENTED_EDGE('',*,*,#876,.T.);
#878=ORIENTED_EDGE('',*,*,#136,.T.);
#879=ORIENTED_EDGE('',*,*,#861,.F.);
#880=ORIENTED_EDGE('',*,*,#250,.T.);
#881=EDGE_LOOP('',(#877,#878,#879,#880));
#882=FACE_BOUND('',#881,.T.);
#883=ADVANCED_FACE('F885',(#882),#870,.T.);
#884=ORIENTED_EDGE('',*,*,#174,.F.);
#885=CARTESIAN_POINT('',(0.,2.,0.));
#886=DIRECTION('',(0.,-1.,0.));
#887=DIRECTION('',(0.,0.,-1.));
#888=AXIS2_PLACEMENT_3D('',#885,#886,#887);
#889=CIRCLE('',#888,5.1);
#890=CARTESIAN_POINT('',(-2.,2.,4.69148164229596));
#891=VERTEX_POINT('',#890);
#892=EDGE_CURVE('E380',#891,#167,#889,.F.);
#893=ORIENTED_EDGE('',*,*,#892,.F.);
#894=DIRECTION('',(0.,-1.,0.));
#895=VECTOR('',#894,1.);
#896=CARTESIAN_POINT('',(-2.,1.,4.69148164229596));
#897=LINE('',#896,#895);
#898=CARTESIAN_POINT('',(-2.,6.,4.69148164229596));
#899=VERTEX_POINT('',#898);
#900=EDGE_CURVE('E383',#899,#891,#897,.T.);
#901=ORIENTED_EDGE('',*,*,#900,.F.);
#902=CARTESIAN_POINT('',(0.,6.,0.));
#903=DIRECTION('',(0.,1.,0.));
#904=DIRECTION('',(0.,0.,1.));
#905=AXIS2_PLACEMENT_3D('',#902,#903,#904);
#906=CIRCLE('',#905,5.1);
#907=CARTESIAN_POINT('',(-2.,6.,-4.69148164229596));
#908=VERTEX_POINT('',#907);
#909=EDGE_CURVE('E311',#908,#899,#906,.T.);
#910=ORIENTED_EDGE('',*,*,#909,.F.);
#911=DIRECTION('',(0.,-1.,0.));
#912=VECTOR('',#911,1.);
#913=CARTESIAN_POINT('',(-2.,1.,-4.69148164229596));
#914=LINE('',#913,#912);
#915=CARTESIAN_POINT('',(-2.,2.,-4.69148164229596));
#916=VERTEX_POINT('',#915);
#917=EDGE_CURVE('E65',#908,#916,#914,.T.);
#918=ORIENTED_EDGE('',*,*,#917,.T.);
#919=CARTESIAN_POINT('',(0.,2.,0.));
#920=DIRECTION('',(0.,1.,0.));
#921=DIRECTION('',(0.,0.,1.));
#922=AXIS2_PLACEMENT_3D('',#919,#920,#921);
#923=CIRCLE('',#922,5.1);
#924=EDGE_CURVE('E51',#916,#213,#923,.F.);
#925=ORIENTED_EDGE('',*,*,#924,.T.);
#926=ORIENTED_EDGE('',*,*,#214,.F.);
#927=ORIENTED_EDGE('',*,*,#603,.T.);
#928=EDGE_LOOP('',(#884,#893,#901,#910,#918,#925,#926,#927));
#929=FACE_BOUND('',#928,.T.);
#930=ADVANCED_FACE('F705',(#929),#846,.T.);
#931=CARTESIAN_POINT('',(0.,8.,0.));
#932=DIRECTION('',(0.,-1.,0.));
#933=DIRECTION('',(0.,0.,-1.));
#934=AXIS2_PLACEMENT_3D('',#931,#932,#933);
#935=CYLINDRICAL_SURFACE('',#934,7.5);
#936=ORIENTED_EDGE('',*,*,#144,.F.);
#937=ORIENTED_EDGE('',*,*,#876,.F.);
#938=ORIENTED_EDGE('',*,*,#246,.F.);
#939=CARTESIAN_POINT('',(0.,6.,0.));
#940=DIRECTION('',(0.,1.,0.));
#941=DIRECTION('',(0.,0.,1.));
#942=AXIS2_PLACEMENT_3D('',#939,#940,#941);
#943=CIRCLE('',#942,7.5);
#944=CARTESIAN_POINT('',(-1.84615384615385,6.,-7.26923076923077));
#945=VERTEX_POINT('',#944);
#946=EDGE_CURVE('E277',#237,#945,#943,.T.);
#947=ORIENTED_EDGE('',*,*,#946,.T.);
#948=CARTESIAN_POINT('',(-1.84615384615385,6.,7.26923076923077));
#949=VERTEX_POINT('',#948);
#950=EDGE_CURVE('E288',#945,#949,#943,.T.);
#951=ORIENTED_EDGE('',*,*,#950,.T.);
#952=EDGE_CURVE('E291',#949,#143,#943,.T.);
#953=ORIENTED_EDGE('',*,*,#952,.T.);
#954=EDGE_LOOP('',(#936,#937,#938,#947,#951,#953));
#955=FACE_BOUND('',#954,.T.);
#956=ADVANCED_FACE('F295',(#955),#935,.T.);
#957=CARTESIAN_POINT('',(0.,6.,0.));
#958=DIRECTION('',(0.,1.,0.));
#959=DIRECTION('',(0.,0.,1.));
#960=AXIS2_PLACEMENT_3D('',#957,#958,#959);
#961=PLANE('',#960);
#962=DIRECTION('',(0.,0.,-1.));
#963=VECTOR('',#962,1.);
#964=CARTESIAN_POINT('',(-2.,6.,8.502));
#965=LINE('',#964,#963);
#966=CARTESIAN_POINT('',(-2.,6.,-6.5));
#967=VERTEX_POINT('',#966);
#968=EDGE_CURVE('E416',#908,#967,#965,.T.);
#969=ORIENTED_EDGE('',*,*,#968,.F.);
#970=ORIENTED_EDGE('',*,*,#909,.T.);
#971=DIRECTION('',(0.,0.,1.));
#972=VECTOR('',#971,1.);
#973=CARTESIAN_POINT('',(-2.,6.,-7.502));
#974=LINE('',#973,#972);
#975=CARTESIAN_POINT('',(-2.,6.,6.5));
#976=VERTEX_POINT('',#975);
#977=EDGE_CURVE('E384',#899,#976,#974,.T.);
#978=ORIENTED_EDGE('',*,*,#977,.T.);
#979=CARTESIAN_POINT('',(0.,6.,6.5));
#980=DIRECTION('',(0.,1.,0.));
#981=DIRECTION('',(0.,0.,1.));
#982=AXIS2_PLACEMENT_3D('',#979,#980,#981);
#983=CIRCLE('',#982,2.);
#984=EDGE_CURVE('E634',#976,#949,#983,.T.);
#985=ORIENTED_EDGE('',*,*,#984,.T.);
#986=ORIENTED_EDGE('',*,*,#950,.F.);
#987=CARTESIAN_POINT('',(0.,6.,-6.5));
#988=DIRECTION('',(0.,1.,0.));
#989=DIRECTION('',(0.,0.,1.));
#990=AXIS2_PLACEMENT_3D('',#987,#988,#989);
#991=CIRCLE('',#990,2.);
#992=EDGE_CURVE('E430',#945,#967,#991,.T.);
#993=ORIENTED_EDGE('',*,*,#992,.T.);
#994=EDGE_LOOP('',(#969,#970,#978,#985,#986,#993));
#995=FACE_BOUND('',#994,.T.);
#996=ADVANCED_FACE('F925',(#995),#961,.F.);
#997=CARTESIAN_POINT('',(-8.,4.,-6.59574082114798));
#998=DIRECTION('',(1.,0.,0.));
#999=DIRECTION('',(0.,1.,0.));
#1000=AXIS2_PLACEMENT_3D('',#997,#998,#999);
#1001=CYLINDRICAL_SURFACE('',#1000,1.);
#1002=CARTESIAN_POINT('',(-2.,4.,-6.59574082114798));
#1003=DIRECTION('',(1.,0.,0.));
#1004=DIRECTION('',(0.,0.,-1.));
#1005=AXIS2_PLACEMENT_3D('',#1002,#1003,#1004);
#1006=CIRCLE('',#1005,1.);
#1007=CARTESIAN_POINT('',(-2.,3.00459370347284,-6.5));
#1008=VERTEX_POINT('',#1007);
#1009=CARTESIAN_POINT('',(-2.,4.99540629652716,-6.5));
#1010=VERTEX_POINT('',#1009);
#1011=EDGE_CURVE('E412',#1008,#1010,#1006,.F.);
#1012=ORIENTED_EDGE('',*,*,#1011,.T.);
#1013=CARTESIAN_POINT('',(-2.,4.99540629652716,-6.5));
#1014=CARTESIAN_POINT('',(-2.00000256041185,4.99791259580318,-6.52604370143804));
#1015=CARTESIAN_POINT('',(-1.99949067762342,4.99939211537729,-6.55217308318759));
#1016=CARTESIAN_POINT('',(-1.99744300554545,5.00030354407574,-6.60441916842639));
#1017=CARTESIAN_POINT('',(-1.99590754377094,4.9997361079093,-6.63053587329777));
#1018=CARTESIAN_POINT('',(-1.98979443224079,4.99499052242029,-6.70834042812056));
#1019=CARTESIAN_POINT('',(-1.98370992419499,4.98779539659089,-6.75976232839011));
#1020=CARTESIAN_POINT('',(-1.967943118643,4.96575152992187,-6.86026849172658));
#1021=CARTESIAN_POINT('',(-1.95826367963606,4.95090886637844,-6.90935457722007));
#1022=CARTESIAN_POINT('',(-1.93602532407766,4.91420910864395,-7.00416234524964));
#1023=CARTESIAN_POINT('',(-1.9234639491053,4.89234601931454,-7.04988111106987));
#1024=CARTESIAN_POINT('',(-1.89562500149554,4.84093295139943,-7.13947419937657));
#1025=CARTESIAN_POINT('',(-1.8802358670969,4.8110256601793,-7.18310790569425));
#1026=CARTESIAN_POINT('',(-1.84845345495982,4.74493462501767,-7.2649514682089));
#1027=CARTESIAN_POINT('',(-1.83205934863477,4.70874565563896,-7.30315676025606));
#1028=CARTESIAN_POINT('',(-1.79790045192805,4.62671303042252,-7.37714310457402));
#1029=CARTESIAN_POINT('',(-1.78016912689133,4.58025808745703,-7.41226544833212));
#1030=CARTESIAN_POINT('',(-1.74704598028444,4.48135784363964,-7.47420044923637));
#1031=CARTESIAN_POINT('',(-1.7316522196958,4.42891757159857,-7.50102001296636));
#1032=CARTESIAN_POINT('',(-1.70765091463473,4.3289604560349,-7.5413350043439));
#1033=CARTESIAN_POINT('',(-1.69832282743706,4.28223226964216,-7.55635333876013));
#1034=CARTESIAN_POINT('',(-1.68375329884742,4.18648883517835,-7.57942780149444));
#1035=CARTESIAN_POINT('',(-1.67850742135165,4.13747613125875,-7.58749148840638));
#1036=CARTESIAN_POINT('',(-1.67280342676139,4.03833914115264,-7.59624741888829));
#1037=CARTESIAN_POINT('',(-1.67236155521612,3.98821165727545,-7.59691465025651));
#1038=CARTESIAN_POINT('',(-1.67637478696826,3.8886102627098,-7.59077017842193));
#1039=CARTESIAN_POINT('',(-1.68083140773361,3.83913655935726,-7.58395615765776));
#1040=CARTESIAN_POINT('',(-1.69368570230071,3.74469374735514,-7.56374844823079));
#1041=CARTESIAN_POINT('',(-1.70188010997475,3.69962265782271,-7.5506926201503));
#1042=CARTESIAN_POINT('',(-1.72121919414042,3.61230356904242,-7.5187012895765));
#1043=CARTESIAN_POINT('',(-1.73236484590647,3.57005650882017,-7.49976384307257));
#1044=CARTESIAN_POINT('',(-1.75798786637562,3.48434224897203,-7.45406460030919));
#1045=CARTESIAN_POINT('',(-1.77270089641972,3.44129251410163,-7.42665383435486));
#1046=CARTESIAN_POINT('',(-1.80318560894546,3.36005884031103,-7.36584043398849));
#1047=CARTESIAN_POINT('',(-1.81895806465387,3.32187851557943,-7.33243339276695));
#1048=CARTESIAN_POINT('',(-1.85248222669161,3.24604938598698,-7.25519218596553));
#1049=CARTESIAN_POINT('',(-1.87020685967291,3.20920028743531,-7.21055536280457));
#1050=CARTESIAN_POINT('',(-1.90374167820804,3.14347081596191,-7.11508125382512));
#1051=CARTESIAN_POINT('',(-1.91955159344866,3.11459156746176,-7.06424309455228));
#1052=CARTESIAN_POINT('',(-1.94764919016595,3.06606334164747,-6.95789108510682));
#1053=CARTESIAN_POINT('',(-1.95996205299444,3.04634768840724,-6.90241459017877));
#1054=CARTESIAN_POINT('',(-1.97998231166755,3.01691642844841,-6.78812034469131));
#1055=CARTESIAN_POINT('',(-1.98769923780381,3.00718009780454,-6.72930978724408));
#1056=CARTESIAN_POINT('',(-1.99517623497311,3.00065361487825,-6.64171572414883));
#1057=CARTESIAN_POINT('',(-1.99698677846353,2.99975226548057,-6.61335481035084));
#1058=CARTESIAN_POINT('',(-1.99939974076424,3.0003632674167,-6.55662985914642));
#1059=CARTESIAN_POINT('',(-2.00000309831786,3.0018737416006,-6.52826584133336));
#1060=CARTESIAN_POINT('',(-2.00000000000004,3.00459370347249,-6.50000000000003));
#1061=B_SPLINE_CURVE_WITH_KNOTS('',3,(#1013,#1014,#1015,#1016,#1017,#1018,#1019,#1020,#1021,
#1022,#1023,#1024,#1025,#1026,#1027,#1028,#1029,#1030,#1031,#1032,#1033,#1034,#1035,#1036,#1037,
#1038,#1039,#1040,#1041,#1042,#1043,#1044,#1045,#1046,#1047,#1048,#1049,#1050,#1051,#1052,#1053,
#1054,#1055,#1056,#1057,#1058,#1059,#1060),.UNSPECIFIED.,.F.,.F.,(4,2,2,2,2,2,2,2,2,2,2,2,2,2,2,
2,2,2,2,2,2,2,2,4),(0.,0.0784411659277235,0.156857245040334,0.31285841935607,0.468735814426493,
0.624746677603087,0.789357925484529,0.954106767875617,1.13588374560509,1.31750910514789,
1.46675881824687,1.61584611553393,1.76543742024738,1.91507507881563,2.05739915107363,
2.19977031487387,2.35849846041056,2.51734374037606,2.69809891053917,2.87887956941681,
3.05832340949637,3.23739384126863,3.32258153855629,3.40770296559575),.UNSPECIFIED.);
#1062=EDGE_CURVE('E644',#1010,#1008,#1061,.T.);
#1063=ORIENTED_EDGE('',*,*,#1062,.T.);
#1064=EDGE_LOOP('',(#1012,#1063));
#1065=FACE_BOUND('',#1064,.T.);
#1066=ORIENTED_EDGE('',*,*,#279,.F.);
#1067=EDGE_LOOP('',(#1066));
#1068=FACE_BOUND('',#1067,.T.);
#1069=ADVANCED_FACE('F935',(#1065,#1068),#1001,.F.);
#1070=CARTESIAN_POINT('',(-2.,2.,8.502));
#1071=DIRECTION('',(1.,0.,0.));
#1072=DIRECTION('',(0.,0.,-1.));
#1073=AXIS2_PLACEMENT_3D('',#1070,#1071,#1072);
#1074=PLANE('',#1073);
#1075=ORIENTED_EDGE('',*,*,#968,.T.);
#1076=DIRECTION('',(0.,-1.,0.));
#1077=VECTOR('',#1076,1.);
#1078=CARTESIAN_POINT('',(-2.,2.,-6.5));
#1079=LINE('',#1078,#1077);
#1080=EDGE_CURVE('E640',#967,#1010,#1079,.T.);
#1081=ORIENTED_EDGE('',*,*,#1080,.T.);
#1082=ORIENTED_EDGE('',*,*,#1011,.F.);
#1083=DIRECTION('',(0.,-1.,0.));
#1084=VECTOR('',#1083,1.);
#1085=CARTESIAN_POINT('',(-2.,2.,-6.5));
#1086=LINE('',#1085,#1084);
#1087=CARTESIAN_POINT('',(-2.,2.,-6.5));
#1088=VERTEX_POINT('',#1087);
#1089=EDGE_CURVE('E637',#1008,#1088,#1086,.T.);
#1090=ORIENTED_EDGE('',*,*,#1089,.T.);
#1091=DIRECTION('',(0.,0.,-1.));
#1092=VECTOR('',#1091,1.);
#1093=CARTESIAN_POINT('',(-2.,2.,8.502));
#1094=LINE('',#1093,#1092);
#1095=EDGE_CURVE('E413',#916,#1088,#1094,.T.);
#1096=ORIENTED_EDGE('',*,*,#1095,.F.);
#1097=ORIENTED_EDGE('',*,*,#917,.F.);
#1098=EDGE_LOOP('',(#1075,#1081,#1082,#1090,#1096,#1097));
#1099=FACE_BOUND('',#1098,.T.);
#1100=ADVANCED_FACE('F770',(#1099),#1074,.F.);
#1101=CARTESIAN_POINT('',(-2.,2.,8.502));
#1102=DIRECTION('',(0.,1.,0.));
#1103=DIRECTION('',(0.,0.,1.));
#1104=AXIS2_PLACEMENT_3D('',#1101,#1102,#1103);
#1105=PLANE('',#1104);
#1106=ORIENTED_EDGE('',*,*,#222,.F.);
#1107=ORIENTED_EDGE('',*,*,#924,.F.);
#1108=ORIENTED_EDGE('',*,*,#1095,.T.);
#1109=CARTESIAN_POINT('',(0.,2.,-6.5));
#1110=DIRECTION('',(0.,1.,0.));
#1111=DIRECTION('',(0.,0.,1.));
#1112=AXIS2_PLACEMENT_3D('',#1109,#1110,#1111);
#1113=CIRCLE('',#1112,2.);
#1114=EDGE_CURVE('E647',#1088,#221,#1113,.F.);
#1115=ORIENTED_EDGE('',*,*,#1114,.T.);
#1116=EDGE_LOOP('',(#1106,#1107,#1108,#1115));
#1117=FACE_BOUND('',#1116,.T.);
#1118=ADVANCED_FACE('F954',(#1117),#1105,.F.);
#1119=CARTESIAN_POINT('',(-2.,6.,8.502));
#1120=DIRECTION('',(0.,-1.,0.));
#1121=DIRECTION('',(0.,0.,-1.));
#1122=AXIS2_PLACEMENT_3D('',#1119,#1120,#1121);
#1123=PLANE('',#1122);
#1124=ORIENTED_EDGE('',*,*,#238,.F.);
#1125=CARTESIAN_POINT('',(0.,6.,-6.5));
#1126=DIRECTION('',(0.,-1.,0.));
#1127=DIRECTION('',(0.,0.,-1.));
#1128=AXIS2_PLACEMENT_3D('',#1125,#1126,#1127);
#1129=CIRCLE('',#1128,2.);
#1130=EDGE_CURVE('E283',#229,#945,#1129,.F.);
#1131=ORIENTED_EDGE('',*,*,#1130,.T.);
#1132=ORIENTED_EDGE('',*,*,#946,.F.);
#1133=EDGE_LOOP('',(#1124,#1131,#1132));
#1134=FACE_BOUND('',#1133,.T.);
#1135=ADVANCED_FACE('F279',(#1134),#1123,.F.);
#1136=CARTESIAN_POINT('',(0.,2.,-6.5));
#1137=DIRECTION('',(0.,-1.,0.));
#1138=DIRECTION('',(0.,0.,-1.));
#1139=AXIS2_PLACEMENT_3D('',#1136,#1137,#1138);
#1140=CYLINDRICAL_SURFACE('',#1139,2.);
#1141=ORIENTED_EDGE('',*,*,#1130,.F.);
#1142=ORIENTED_EDGE('',*,*,#230,.T.);
#1143=ORIENTED_EDGE('',*,*,#1114,.F.);
#1144=ORIENTED_EDGE('',*,*,#1089,.F.);
#1145=ORIENTED_EDGE('',*,*,#1062,.F.);
#1146=ORIENTED_EDGE('',*,*,#1080,.F.);
#1147=ORIENTED_EDGE('',*,*,#992,.F.);
#1148=EDGE_LOOP('',(#1141,#1142,#1143,#1144,#1145,#1146,#1147));
#1149=FACE_BOUND('',#1148,.T.);
#1150=ADVANCED_FACE('F781',(#1149),#1140,.T.);
#1151=CARTESIAN_POINT('',(-2.,6.,-7.502));
#1152=DIRECTION('',(0.,1.,0.));
#1153=DIRECTION('',(0.,0.,1.));
#1154=AXIS2_PLACEMENT_3D('',#1151,#1152,#1153);
#1155=PLANE('',#1154);
#1156=CARTESIAN_POINT('',(0.,6.,6.5));
#1157=DIRECTION('',(0.,1.,0.));
#1158=DIRECTION('',(0.,0.,1.));
#1159=AXIS2_PLACEMENT_3D('',#1156,#1157,#1158);
#1160=CIRCLE('',#1159,2.);
#1161=EDGE_CURVE('E631',#949,#151,#1160,.T.);
#1162=ORIENTED_EDGE('',*,*,#1161,.T.);
#1163=ORIENTED_EDGE('',*,*,#152,.T.);
#1164=ORIENTED_EDGE('',*,*,#952,.F.);
#1165=EDGE_LOOP('',(#1162,#1163,#1164));
#1166=FACE_BOUND('',#1165,.T.);
#1167=ADVANCED_FACE('F978',(#1166),#1155,.T.);
#1168=CARTESIAN_POINT('',(-2.,2.,-7.502));
#1169=DIRECTION('',(0.,-1.,0.));
#1170=DIRECTION('',(0.,0.,-1.));
#1171=AXIS2_PLACEMENT_3D('',#1168,#1169,#1170);
#1172=PLANE('',#1171);
#1173=ORIENTED_EDGE('',*,*,#892,.T.);
#1174=ORIENTED_EDGE('',*,*,#168,.T.);
#1175=CARTESIAN_POINT('',(0.,2.,6.5));
#1176=DIRECTION('',(0.,-1.,0.));
#1177=DIRECTION('',(0.,0.,-1.));
#1178=AXIS2_PLACEMENT_3D('',#1175,#1176,#1177);
#1179=CIRCLE('',#1178,2.);
#1180=CARTESIAN_POINT('',(-2.,2.,6.5));
#1181=VERTEX_POINT('',#1180);
#1182=EDGE_CURVE('E315',#159,#1181,#1179,.T.);
#1183=ORIENTED_EDGE('',*,*,#1182,.T.);
#1184=DIRECTION('',(0.,0.,1.));
#1185=VECTOR('',#1184,1.);
#1186=CARTESIAN_POINT('',(-2.,2.,-7.502));
#1187=LINE('',#1186,#1185);
#1188=EDGE_CURVE('E379',#891,#1181,#1187,.T.);
#1189=ORIENTED_EDGE('',*,*,#1188,.F.);
#1190=EDGE_LOOP('',(#1173,#1174,#1183,#1189));
#1191=FACE_BOUND('',#1190,.T.);
#1192=ADVANCED_FACE('F763',(#1191),#1172,.T.);
#1193=CARTESIAN_POINT('',(-2.,2.,-7.502));
#1194=DIRECTION('',(-1.,0.,0.));
#1195=DIRECTION('',(0.,0.,1.));
#1196=AXIS2_PLACEMENT_3D('',#1193,#1194,#1195);
#1197=PLANE('',#1196);
#1198=ORIENTED_EDGE('',*,*,#1188,.T.);
#1199=DIRECTION('',(0.,-1.,0.));
#1200=VECTOR('',#1199,1.);
#1201=CARTESIAN_POINT('',(-2.,6.,6.5));
#1202=LINE('',#1201,#1200);
#1203=CARTESIAN_POINT('',(-2.,3.00459370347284,6.5));
#1204=VERTEX_POINT('',#1203);
#1205=EDGE_CURVE('E624',#1181,#1204,#1202,.F.);
#1206=ORIENTED_EDGE('',*,*,#1205,.T.);
#1207=CARTESIAN_POINT('',(-2.,4.,6.59574082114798));
#1208=DIRECTION('',(-1.,0.,0.));
#1209=DIRECTION('',(0.,0.,1.));
#1210=AXIS2_PLACEMENT_3D('',#1207,#1208,#1209);
#1211=CIRCLE('',#1210,1.);
#1212=CARTESIAN_POINT('',(-2.,4.99540629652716,6.5));
#1213=VERTEX_POINT('',#1212);
#1214=EDGE_CURVE('E391',#1213,#1204,#1211,.T.);
#1215=ORIENTED_EDGE('',*,*,#1214,.F.);
#1216=DIRECTION('',(0.,-1.,0.));
#1217=VECTOR('',#1216,1.);
#1218=CARTESIAN_POINT('',(-2.,6.,6.5));
#1219=LINE('',#1218,#1217);
#1220=EDGE_CURVE('E621',#1213,#976,#1219,.F.);
#1221=ORIENTED_EDGE('',*,*,#1220,.T.);
#1222=ORIENTED_EDGE('',*,*,#977,.F.);
#1223=ORIENTED_EDGE('',*,*,#900,.T.);
#1224=EDGE_LOOP('',(#1198,#1206,#1215,#1221,#1222,#1223));
#1225=FACE_BOUND('',#1224,.T.);
#1226=ADVANCED_FACE('F759',(#1225),#1197,.T.);
#1227=CARTESIAN_POINT('',(-8.,4.,6.59574082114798));
#1228=DIRECTION('',(1.,0.,0.));
#1229=DIRECTION('',(0.,1.,0.));
#1230=AXIS2_PLACEMENT_3D('',#1227,#1228,#1229);
#1231=CYLINDRICAL_SURFACE('',#1230,1.);
#1232=ORIENTED_EDGE('',*,*,#1214,.T.);
#1233=CARTESIAN_POINT('',(-2.,3.00459370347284,6.5));
#1234=CARTESIAN_POINT('',(-2.00000256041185,3.00208740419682,6.52604370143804));
#1235=CARTESIAN_POINT('',(-1.99949067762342,3.00060788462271,6.55217308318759));
#1236=CARTESIAN_POINT('',(-1.99744300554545,2.99969645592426,6.60441916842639));
#1237=CARTESIAN_POINT('',(-1.99590754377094,3.0002638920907,6.63053587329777));
#1238=CARTESIAN_POINT('',(-1.98979443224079,3.00500947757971,6.70834042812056));
#1239=CARTESIAN_POINT('',(-1.98370992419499,3.01220460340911,6.75976232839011));
#1240=CARTESIAN_POINT('',(-1.967943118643,3.03424847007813,6.86026849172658));
#1241=CARTESIAN_POINT('',(-1.95826367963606,3.04909113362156,6.90935457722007));
#1242=CARTESIAN_POINT('',(-1.93602532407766,3.08579089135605,7.00416234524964));
#1243=CARTESIAN_POINT('',(-1.9234639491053,3.10765398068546,7.04988111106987));
#1244=CARTESIAN_POINT('',(-1.89562500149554,3.15906704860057,7.13947419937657));
#1245=CARTESIAN_POINT('',(-1.8802358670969,3.1889743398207,7.18310790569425));
#1246=CARTESIAN_POINT('',(-1.84845345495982,3.25506537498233,7.2649514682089));
#1247=CARTESIAN_POINT('',(-1.83205934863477,3.29125434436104,7.30315676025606));
#1248=CARTESIAN_POINT('',(-1.79790045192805,3.37328696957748,7.37714310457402));
#1249=CARTESIAN_POINT('',(-1.78016912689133,3.41974191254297,7.41226544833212));
#1250=CARTESIAN_POINT('',(-1.74704598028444,3.51864215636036,7.47420044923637));
#1251=CARTESIAN_POINT('',(-1.7316522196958,3.57108242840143,7.50102001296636));
#1252=CARTESIAN_POINT('',(-1.70765091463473,3.6710395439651,7.5413350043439));
#1253=CARTESIAN_POINT('',(-1.69832282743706,3.71776773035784,7.55635333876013));
#1254=CARTESIAN_POINT('',(-1.68375329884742,3.81351116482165,7.57942780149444));
#1255=CARTESIAN_POINT('',(-1.67850742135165,3.86252386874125,7.58749148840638));
#1256=CARTESIAN_POINT('',(-1.67280342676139,3.96166085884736,7.59624741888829));
#1257=CARTESIAN_POINT('',(-1.67236155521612,4.01178834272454,7.59691465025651));
#1258=CARTESIAN_POINT('',(-1.67637478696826,4.1113897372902,7.59077017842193));
#1259=CARTESIAN_POINT('',(-1.68083140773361,4.16086344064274,7.58395615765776));
#1260=CARTESIAN_POINT('',(-1.69368570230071,4.25530625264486,7.56374844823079));
#1261=CARTESIAN_POINT('',(-1.70188010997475,4.30037734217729,7.5506926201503));
#1262=CARTESIAN_POINT('',(-1.72121919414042,4.38769643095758,7.5187012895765));
#1263=CARTESIAN_POINT('',(-1.73236484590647,4.42994349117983,7.49976384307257));
#1264=CARTESIAN_POINT('',(-1.75798786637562,4.51565775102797,7.45406460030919));
#1265=CARTESIAN_POINT('',(-1.77270089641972,4.55870748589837,7.42665383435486));
#1266=CARTESIAN_POINT('',(-1.80318560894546,4.63994115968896,7.36584043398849));
#1267=CARTESIAN_POINT('',(-1.81895806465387,4.67812148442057,7.33243339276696));
#1268=CARTESIAN_POINT('',(-1.85248222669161,4.75395061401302,7.25519218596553));
#1269=CARTESIAN_POINT('',(-1.87020685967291,4.79079971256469,7.21055536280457));
#1270=CARTESIAN_POINT('',(-1.90374167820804,4.85652918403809,7.11508125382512));
#1271=CARTESIAN_POINT('',(-1.91955159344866,4.88540843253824,7.06424309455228));
#1272=CARTESIAN_POINT('',(-1.94764919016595,4.93393665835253,6.95789108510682));
#1273=CARTESIAN_POINT('',(-1.95996205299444,4.95365231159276,6.90241459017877));
#1274=CARTESIAN_POINT('',(-1.97998231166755,4.98308357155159,6.78812034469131));
#1275=CARTESIAN_POINT('',(-1.98769923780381,4.99281990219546,6.72930978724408));
#1276=CARTESIAN_POINT('',(-1.99517623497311,4.99934638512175,6.64171572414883));
#1277=CARTESIAN_POINT('',(-1.99698677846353,5.00024773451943,6.61335481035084));
#1278=CARTESIAN_POINT('',(-1.99939974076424,4.9996367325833,6.55662985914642));
#1279=CARTESIAN_POINT('',(-2.00000309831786,4.9981262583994,6.52826584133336));
#1280=CARTESIAN_POINT('',(-2.00000000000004,4.99540629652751,6.50000000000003));
#1281=B_SPLINE_CURVE_WITH_KNOTS('',3,(#1233,#1234,#1235,#1236,#1237,#1238,#1239,#1240,#1241,
#1242,#1243,#1244,#1245,#1246,#1247,#1248,#1249,#1250,#1251,#1252,#1253,#1254,#1255,#1256,#1257,
#1258,#1259,#1260,#1261,#1262,#1263,#1264,#1265,#1266,#1267,#1268,#1269,#1270,#1271,#1272,#1273,
#1274,#1275,#1276,#1277,#1278,#1279,#1280),.UNSPECIFIED.,.F.,.F.,(4,2,2,2,2,2,2,2,2,2,2,2,2,2,2,
2,2,2,2,2,2,2,2,4),(0.,0.0784411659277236,0.156857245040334,0.31285841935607,0.468735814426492,
0.624746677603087,0.789357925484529,0.954106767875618,1.13588374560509,1.31750910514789,
1.46675881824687,1.61584611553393,1.76543742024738,1.91507507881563,2.05739915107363,
2.19977031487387,2.35849846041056,2.51734374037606,2.69809891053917,2.87887956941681,
3.05832340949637,3.23739384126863,3.32258153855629,3.40770296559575),.UNSPECIFIED.);
#1282=EDGE_CURVE('E628',#1204,#1213,#1281,.T.);
#1283=ORIENTED_EDGE('',*,*,#1282,.T.);
#1284=EDGE_LOOP('',(#1232,#1283));
#1285=FACE_BOUND('',#1284,.T.);
#1286=ORIENTED_EDGE('',*,*,#185,.T.);
#1287=EDGE_LOOP('',(#1286));
#1288=FACE_BOUND('',#1287,.T.);
#1289=ADVANCED_FACE('F762',(#1285,#1288),#1231,.F.);
#1290=CARTESIAN_POINT('',(0.,0.,6.5));
#1291=DIRECTION('',(0.,1.,0.));
#1292=DIRECTION('',(0.,0.,1.));
#1293=AXIS2_PLACEMENT_3D('',#1290,#1291,#1292);
#1294=CYLINDRICAL_SURFACE('',#1293,2.);
#1295=ORIENTED_EDGE('',*,*,#1282,.F.);
#1296=ORIENTED_EDGE('',*,*,#1205,.F.);
#1297=ORIENTED_EDGE('',*,*,#1182,.F.);
#1298=ORIENTED_EDGE('',*,*,#160,.T.);
#1299=ORIENTED_EDGE('',*,*,#1161,.F.);
#1300=ORIENTED_EDGE('',*,*,#984,.F.);
#1301=ORIENTED_EDGE('',*,*,#1220,.F.);
#1302=EDGE_LOOP('',(#1295,#1296,#1297,#1298,#1299,#1300,#1301));
#1303=FACE_BOUND('',#1302,.T.);
#1304=ADVANCED_FACE('F768',(#1303),#1294,.T.);
#1305=CARTESIAN_POINT('',(0.,13.,0.));
#1306=DIRECTION('',(0.,1.,0.));
#1307=DIRECTION('',(0.,0.,1.));
#1308=AXIS2_PLACEMENT_3D('',#1305,#1306,#1307);
#1309=PLANE('',#1308);
#1310=ORIENTED_EDGE('',*,*,#853,.T.);
#1311=ORIENTED_EDGE('',*,*,#120,.T.);
#1312=ORIENTED_EDGE('',*,*,#834,.F.);
#1313=ORIENTED_EDGE('',*,*,#262,.T.);
#1314=EDGE_LOOP('',(#1310,#1311,#1312,#1313));
#1315=FACE_BOUND('',#1314,.T.);
#1316=ADVANCED_FACE('F49',(#1315),#1309,.T.);
#1317=CLOSED_SHELL('',(#87,#189,#283,#325,#356,#389,#411,#453,#484,#517,#539,#579,#656,#674,
#684,#715,#775,#787,#799,#811,#823,#841,#865,#883,#930,#956,#996,#1069,#1100,#1118,#1135,#1150,
#1167,#1192,#1226,#1289,#1304,#1316));
#1318=MANIFOLD_SOLID_BREP('B2',#1317);
#1319=ADVANCED_BREP_SHAPE_REPRESENTATION('',(#18,#1318),#14);
#1320=SHAPE_DEFINITION_REPRESENTATION(#9,#1319);
ENDSEC;
END-ISO-10303-21;
